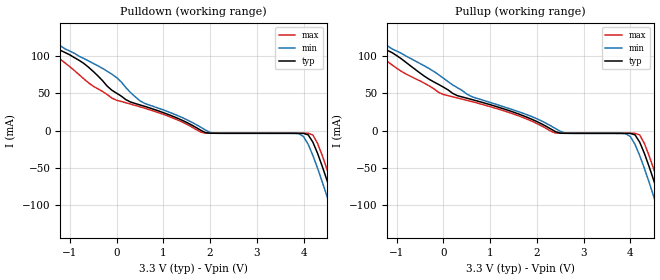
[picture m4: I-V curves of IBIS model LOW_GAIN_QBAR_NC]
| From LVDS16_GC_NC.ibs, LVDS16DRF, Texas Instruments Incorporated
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|   Q_bar Output Model
[Model]   LOW_GAIN_QBAR_NC
Model_type   Output_ECL
| Signals   Q/
Vmeas = 2.0V   |Reference voltage for timing measurements
Cref = 0pF   |Timing specification test load capacitance value
| variable   typ   min   max
C_comp   0.6pF   0.4pF   0.7pF
|   typ   min   max
[Temperature Range]   25   -40   85
[Voltage range]   3.3V   3.0V   3.6V
[Pulldown]
|Voltage I(typ)   I(min)   I(max)
| Note that the[Pulldown]voltage table for (P)ECL is referenced
| to Vcc and is calculated using Vtable=Vcc - Vmeasured.
-3.3V     261mA      299mA      227mA
-2.3V     162mA      199mA      140mA
-1.7V     125mA      144mA      119mA
-100mV    54.3mA     75.9mA     43.7mA
500mV     34.5mA     40.1mA     32mA
1.8V      398uA      4.5mA      -2.15mA
3.9V      -3.75mA    -4.27mA    -3.65mA
4.2V      -15.6mA    -33.5mA    -5.94mA
4.7V      -106mA     -129mA     -90.8mA
4.9V      -148mA     -171mA     -132mA
5V        -170mA     -193mA     -154mA
6.6V      -556mA     -581mA     -538mA
[Pullup]
|Voltage   I(typ)   I(min)   I(max)
| Note that the[Pullup]voltage table is referenced to Vcc
| and is calculated using Vtable=Vcc - Vmeasured.
-3.3V     260mA      298mA      226mA
-2.3V     161mA      199mA      140mA
-1.7V     124mA      143mA      116mA
-100mV    61.4mA     74.4mA     50.8mA
600mV     41.5mA     45.4mA     38.7mA
2.4V      -1.58mA    2.54mA     -3.42mA
3.9V      -3.75mA    -4.27mA    -3.65mA
4.2V      -15.6mA    -33.5mA    -5.94mA
4.7V      -106mA     -129mA     -90.8mA
4.9V      -148mA     -171mA     -132mA
5V        -170mA     -193mA     -154mA
6.6V      -556mA     -581mA     -538mA
[Ramp]
|   typ   min   max
dV/dt_r   0.314/215ps   0.313/245ps   0.310/205ps
dV/dt_f   0.314/195ps   0.313/215ps   0.310/180ps
